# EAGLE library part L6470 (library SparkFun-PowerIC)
3A RMS/7A peak bipolar stepper motor driver with SPI control and step input in HTSSOP-28 package. IC-10648

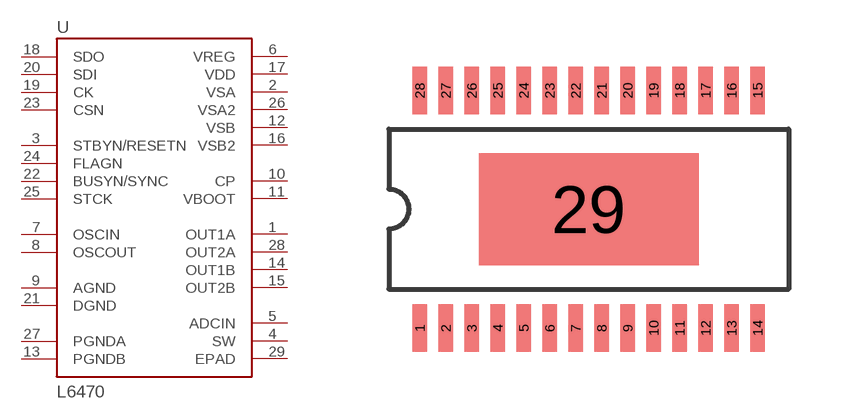
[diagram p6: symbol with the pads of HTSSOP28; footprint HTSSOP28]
Designator prefix U

## L6470 (PROD_ID: IC-10648)  [HTSSOP28]
1  OUT1A
2  VSA
3  STBYN/RESETN
4  SW
5  ADCIN
6  VREG
7  OSCIN
8  OSCOUT
9  AGND
10  CP
11  VBOOT
12  VSB
13  PGNDB
14  OUT1B
15  OUT2B
16  VSB2
17  VDD
18  SDO
19  CK
20  SDI
21  DGND
22  BUSYN/SYNC
23  CSN
24  FLAGN
25  STCK
26  VSA2
27  PGNDA
28  OUT2A
29  EPAD

## Footprint HTSSOP28 (pad centres in mm)
smd 0.36 x 1.19: 1 -4.225,-2.97; 2 -3.575,-2.97; 3 -2.925,-2.97; 4 -2.275,-2.97; 5 -1.625,-2.97; 6 -0.975,-2.97; 7 -0.325,-2.97; 8 0.325,-2.97; 9 0.975,-2.97; 10 1.625,-2.97; 11 2.275,-2.97; 12 2.925,-2.97; 13 3.575,-2.97; 14 4.225,-2.97; 15 4.225,2.97; 16 3.575,2.97; 17 2.925,2.97; 18 2.275,2.97; 19 1.625,2.97; 20 0.975,2.97; 21 0.325,2.97; 22 -0.325,2.97; 23 -0.975,2.97; 24 -1.625,2.97; 25 -2.275,2.97; 26 -2.925,2.97; 27 -3.575,2.97; 28 -4.225,2.97
smd 5.5 x 2.8: 29 0,0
